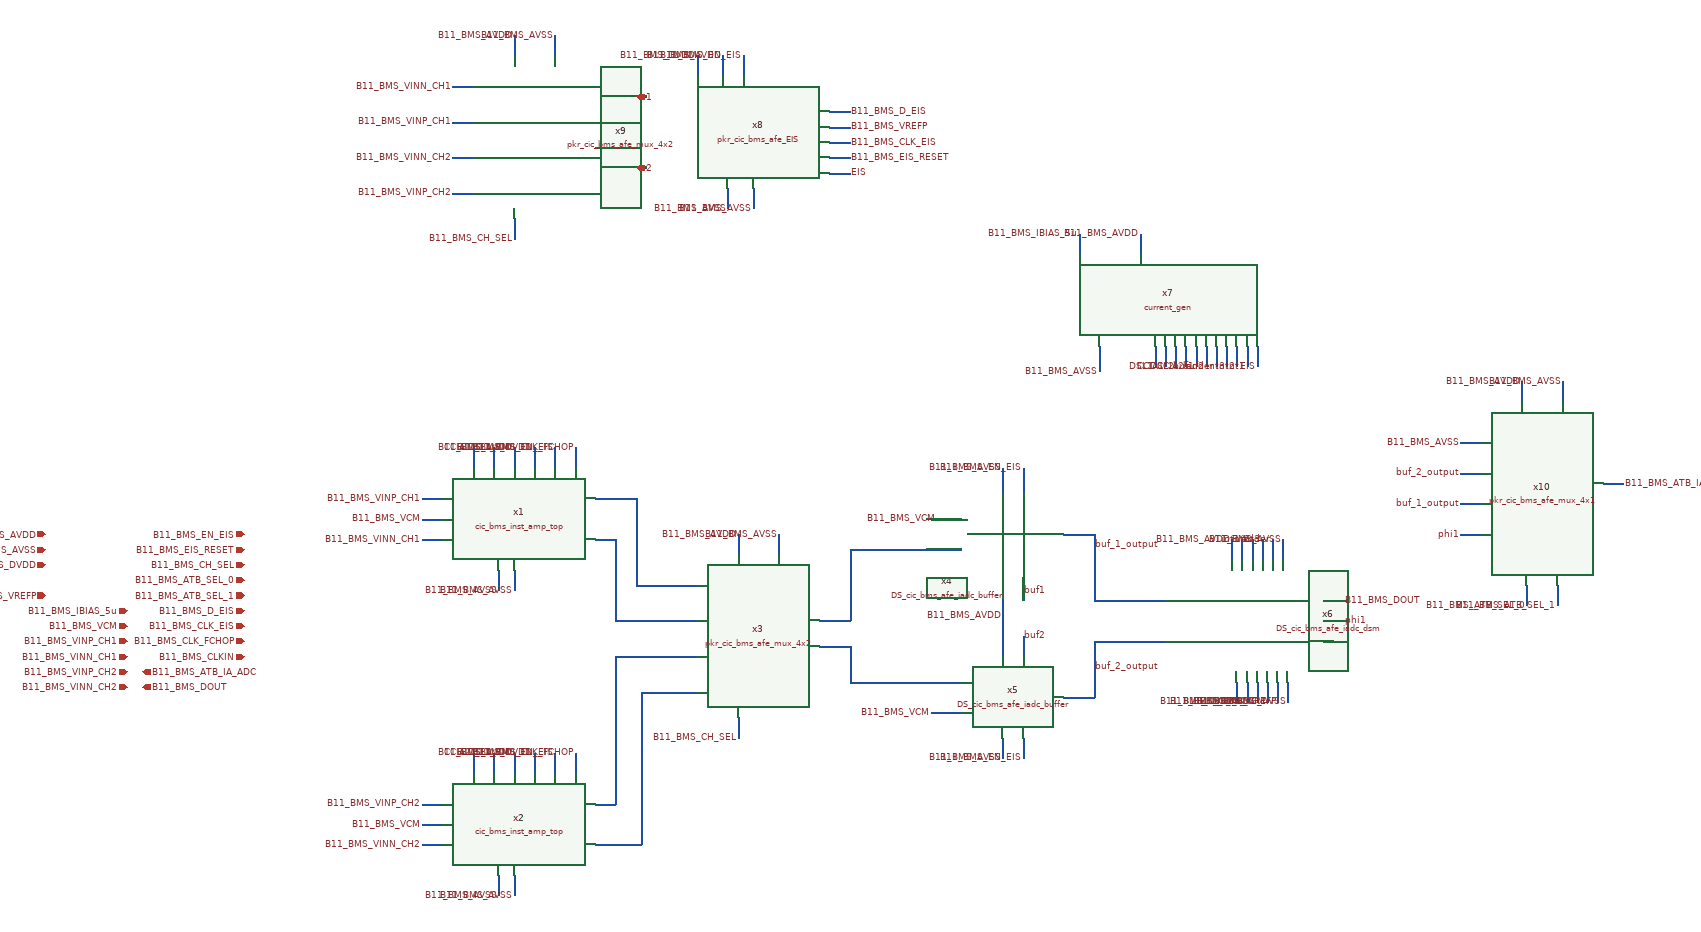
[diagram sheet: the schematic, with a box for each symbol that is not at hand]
v {xschem version=3.4.8RC file_version=1.3}
G {}
K {}
V {}
S {}
F {}
E {}
P 4 1 1090 40 {}
N 390 -460 390 -420 {
lab=B11_BMS_AVDD}
N 430 -460 430 -420 {
lab=B11_BMS_DVDD}
N 510 -460 510 -420 {
lab=B11_BMS_CLK_FCHOP}
N 550 -280 590 -280 {
lab=#net1}
N 360 -220 360 -180 {
lab=B11_BMS_AVSS}
N 550 -360 630 -360 {
lab=#net2}
N 210 -360 250 -360 {
lab=B11_BMS_VINP_CH1}
N 210 -320 250 -320 {
lab=B11_BMS_VCM}
N 210 -280 250 -280 {
lab=B11_BMS_VINN_CH1}
N 310 140 310 180 {
lab=CCIA2}
N 390 140 390 180 {
lab=B11_BMS_AVDD}
N 430 140 430 180 {
lab=B11_BMS_DVDD}
N 470 140 470 180 {
lab=B11_BMS_EN_EIS}
N 510 140 510 180 {
lab=B11_BMS_CLK_FCHOP}
N 550 320 640 320 {
lab=#net3}
N 360 380 360 420 {
lab=B11_BMS_AVSS}
N 550 240 590 240 {
lab=#net4}
N 210 240 250 240 {
lab=B11_BMS_VINP_CH2}
N 210 280 250 280 {
lab=B11_BMS_VCM}
N 210 320 250 320 {
lab=B11_BMS_VINN_CH2}
N 590 -280 590 -120 {
lab=#net1}
N 630 -360 630 -190 {
lab=#net2}
N 350 -460 350 -420 {
lab=DSL1}
N 640 30 640 320 {lab=#net3}
N 590 -40 590 240 {lab=#net4}
N 470 -460 470 -420 {
lab=B11_BMS_EN_EIS}
N 310 -460 310 -420 {
lab=CCIA1}
N 350 140 350 180 {
lab=DSL2}
N 630 -190 750 -190 {lab=#net2}
N 590 -120 750 -120 {lab=#net1}
N 590 -50 750 -50 {lab=#net4}
N 590 -50 590 -40 {lab=#net4}
N 640 20 640 30 {lab=#net3}
N 640 20 750 20 {lab=#net3}
N 830 -290 830 -250 {
lab=B11_BMS_AVDD}
N 830 70 830 110 {
lab=B11_BMS_CH_SEL}
N 910 -290 910 -250 {
lab=B11_BMS_AVSS}
N 990 -120 1050 -120 {lab=#net5}
N 990 -70 1050 -70 {lab=#net6}
N 1050 -260 1050 -120 {lab=#net5}
N 1050 -260 1270 -260 {lab=#net5}
N 1050 -70 1050 0 {lab=#net6}
N 1050 -0 1270 0 {lab=#net6}
N 1210 60 1270 60 {lab=B11_BMS_VCM}
N 1210 -320 1270 -320 {lab=B11_BMS_VCM}
N 1350 -210 1350 -50 {lab=B11_BMS_AVDD}
N 1390 -210 1390 -160 {lab=buf1}
N 1390 -90 1390 -50 {lab=buf2}
N 1350 110 1350 150 {lab=B11_BMS_AVSS}
N 1390 110 1390 150 {lab=B11_BMS_EN_EIS}
N 1470 30 1530 30 {lab=buf_2_output}
N 1470 -290 1530 -290 {lab=buf_1_output}
N 1350 -420 1350 -370 {lab=B11_BMS_AVSS}
N 1390 -420 1390 -370 {lab=B11_BMS_EN_EIS}
N 1530 -290 1530 -160 {lab=buf_1_output}
N 1530 -160 1670 -160 {lab=buf_1_output}
N 1530 -80 1530 30 {lab=buf_2_output}
N 1530 -80 1670 -80 {lab=buf_2_output}
N 1900 -280 1900 -240 {
lab=B11_BMS_AVSS}
N 1800 -280 1800 -240 {
lab=B11_BMS_AVDD}
N 1810 0 1810 40 {
lab=B11_BMS_DVDD}
N 1830 0 1830 40 {
lab=B11_BMS_CLKIN}
N 1880 -280 1880 -240 {
lab=adder}
N 1860 -280 1860 -240 {
lab=int3}
N 1840 -280 1840 -240 {
lab=int2}
N 1820 -280 1820 -240 {
lab=int1}
N 1890 0 1890 40 {
lab=B11_BMS_VREFP}
N 1870 0 1870 40 {
lab=B11_BMS_VCM}
N 1980 -160 2020 -160 {
lab=B11_BMS_DOUT}
N 1980 -120 2020 -120 {
lab=phi1}
N 1980 -80 2000 -80 {lab=#net7}
N 1910 0 1910 40 {lab=B11_BMS_AVSS}
N 1650 -660 1650 -620 {
lab=DSL1}
N 1670 -660 1670 -620 {
lab=CCIA1}
N 1690 -660 1690 -620 {
lab=DSL2}
N 1710 -660 1710 -620 {
lab=CCIA2}
N 1730 -660 1730 -620 {
lab=buf1}
N 1750 -660 1750 -620 {
lab=buf2}
N 1770 -660 1770 -620 {
lab=adder}
N 1790 -660 1790 -620 {
lab=int3}
N 1810 -660 1810 -620 {
lab=int2}
N 1830 -660 1830 -620 {
lab=int1}
N 1620 -880 1620 -840 {lab=B11_BMS_AVDD}
N 1540 -660 1540 -610 {lab=B11_BMS_AVSS}
N 1500 -880 1500 -840 {lab=B11_BMS_IBIAS_5u}
N 270 -1100 310 -1100 {
lab=B11_BMS_VINP_CH1}
N 270 -1170 310 -1170 {
lab=B11_BMS_VINN_CH1}
N 270 -960 310 -960 {
lab=B11_BMS_VINP_CH2}
N 270 -1030 310 -1030 {
lab=B11_BMS_VINN_CH2}
N 390 -910 390 -870 {
lab=B11_BMS_CH_SEL}
N 1850 -660 1850 -620 {
lab=EIS}
N 390 -1270 390 -1230 {
lab=B11_BMS_AVDD}
N 470 -1270 470 -1230 {
lab=B11_BMS_AVSS}
N 550 -1100 590 -1100 {lab=1}
N 550 -1050 620 -1050 {lab=2}
N 620 -1150 650 -1150 {lab=1}
N 590 -1100 620 -1100 {lab=1}
N 620 -1150 620 -1100 {lab=1}
N 620 -1050 620 -1010 {lab=2}
N 620 -1010 650 -1010 {lab=2}
N 840 -1230 840 -1190 {
lab=B11_BMS_EN_EIS}
N 800 -1230 800 -1190 {
lab=B11_BMS_AVDD}
N 750 -1230 750 -1190 {
lab=B11_BMS_DVDD}
N 1010 -1000 1050 -1000 {
lab=EIS}
N 1010 -1030 1050 -1030 {
lab=B11_BMS_EIS_RESET}
N 1010 -1060 1050 -1060 {
lab=B11_BMS_CLK_EIS}
N 1010 -1120 1050 -1120 {
lab=B11_BMS_D_EIS}
N 1010 -1090 1050 -1090 {
lab=B11_BMS_VREFP}
N 860 -970 860 -930 {
lab=B11_BMS_AVSS}
N 2370 -590 2370 -550 {
lab=B11_BMS_AVDD}
N 2450 -590 2450 -550 {lab=B11_BMS_AVSS}
N 2380 -190 2380 -150 {
lab=B11_BMS_ATB_SEL_0}
N 2440 -190 2440 -150 {
lab=B11_BMS_ATB_SEL_1}
N 2530 -390 2570 -390 {
lab=B11_BMS_ATB_IA_ADC}
N 2250 -410 2290 -410 {
lab=buf_2_output}
N 2250 -350 2290 -350 {
lab=buf_1_output}
N 2250 -290 2290 -290 {
lab=phi1}
N 2250 -470 2290 -470 {
lab=B11_BMS_AVSS}
N 390 380 390 420 {
lab=B11_BMS_AVSS}
N 390 -220 390 -180 {
lab=B11_BMS_AVSS}
N 810 -970 810 -930 {
lab=B11_BMS_AVSS}
N 1850 0 1850 40 {
lab=B11_BMS_AVSS}
C {TOP_LEVEL/CCIA/cic_bms_inst_amp_top.sym} 400 -320 0 0 {name=x1}
C {lab_pin.sym} 360 -180 3 0 {name=p23 sig_type=std_logic lab=B11_BMS_AVSS}
C {lab_pin.sym} 390 -460 1 0 {name=p27 sig_type=std_logic lab=B11_BMS_AVDD}
C {lab_pin.sym} 430 -460 1 0 {name=p29 sig_type=std_logic lab=B11_BMS_DVDD}
C {lab_pin.sym} 510 -460 1 0 {name=p34 sig_type=std_logic lab=B11_BMS_CLK_FCHOP}
C {lab_pin.sym} 210 -320 0 0 {name=p36 sig_type=std_logic lab=B11_BMS_VCM}
C {lab_pin.sym} 360 420 3 0 {name=p24 sig_type=std_logic lab=B11_BMS_AVSS}
C {lab_pin.sym} 390 140 1 0 {name=p25 sig_type=std_logic lab=B11_BMS_AVDD}
C {lab_pin.sym} 430 140 1 0 {name=p26 sig_type=std_logic lab=B11_BMS_DVDD}
C {lab_pin.sym} 510 140 1 0 {name=p33 sig_type=std_logic lab=B11_BMS_CLK_FCHOP}
C {lab_pin.sym} 210 280 0 0 {name=p35 sig_type=std_logic lab=B11_BMS_VCM}
C {lab_pin.sym} 470 140 1 0 {name=p44 sig_type=std_logic lab=B11_BMS_EN_EIS}
C {lab_pin.sym} 210 240 0 0 {name=p46 sig_type=std_logic lab=B11_BMS_VINP_CH2}
C {lab_pin.sym} 210 320 0 0 {name=p47 sig_type=std_logic lab=B11_BMS_VINN_CH2}
C {lab_pin.sym} 210 -360 0 0 {name=p48 sig_type=std_logic lab=B11_BMS_VINP_CH1}
C {lab_pin.sym} 210 -280 0 0 {name=p49 sig_type=std_logic lab=B11_BMS_VINN_CH1}
C {lab_pin.sym} 310 140 1 0 {name=p70 sig_type=std_logic lab=CCIA2}
C {lab_pin.sym} 350 -460 1 0 {name=p71 sig_type=std_logic lab=DSL1}
C {lab_pin.sym} 470 -460 1 0 {name=p88 sig_type=std_logic lab=B11_BMS_EN_EIS}
C {lab_pin.sym} 310 -460 1 0 {name=p1 sig_type=std_logic lab=CCIA1}
C {lab_pin.sym} 350 140 1 0 {name=p2 sig_type=std_logic lab=DSL2}
C {TOP_LEVEL/CCIA/cic_bms_inst_amp_top.sym} 400 280 0 0 {name=x2}
C {TOP_LEVEL/MUX/mux_diffrential/pkr_cic_bms_afe_mux_4x2.sym} 710 -90 0 0 {name=x3}
C {lab_pin.sym} 830 -290 1 0 {name=p11 sig_type=std_logic lab=B11_BMS_AVDD}
C {lab_pin.sym} 830 110 3 0 {name=p87 sig_type=std_logic lab=B11_BMS_CH_SEL}
C {lab_pin.sym} 910 -290 1 0 {name=p13 sig_type=std_logic lab=B11_BMS_AVSS}
C {TOP_LEVEL/Buffer/DS_cic_bms_afe_iadc_buffer.sym} 1370 -290 2 1 {name=x4}
C {TOP_LEVEL/Buffer/DS_cic_bms_afe_iadc_buffer.sym} 1370 30 0 0 {name=x5}
C {lab_pin.sym} 1350 -420 1 0 {name=p14 sig_type=std_logic lab=B11_BMS_AVSS}
C {lab_pin.sym} 1350 150 3 0 {name=p15 sig_type=std_logic lab=B11_BMS_AVSS}
C {lab_pin.sym} 1390 150 3 0 {name=p22 sig_type=std_logic lab=B11_BMS_EN_EIS}
C {lab_pin.sym} 1390 -420 1 0 {name=p28 sig_type=std_logic lab=B11_BMS_EN_EIS}
C {lab_pin.sym} 1220 -320 0 0 {name=p30 sig_type=std_logic lab=B11_BMS_VCM}
C {lab_pin.sym} 1210 60 0 0 {name=p31 sig_type=std_logic lab=B11_BMS_VCM}
C {lab_pin.sym} 1390 -180 2 0 {name=p32 sig_type=std_logic lab=buf1}
C {lab_pin.sym} 1390 -90 2 0 {name=p37 sig_type=std_logic lab=buf2}
C {lab_pin.sym} 1350 -130 0 0 {name=p42 sig_type=std_logic lab=B11_BMS_AVDD}
C {TOP_LEVEL/DSM/DS_cic_bms_afe_iadc_dsm.sym} 1830 -120 0 0 {name=x6}
C {lab_pin.sym} 1900 -280 1 0 {name=p53 sig_type=std_logic lab=B11_BMS_AVSS}
C {lab_pin.sym} 1800 -280 1 0 {name=p54 sig_type=std_logic lab=B11_BMS_AVDD}
C {lab_pin.sym} 1810 40 3 0 {name=p56 sig_type=std_logic lab=B11_BMS_DVDD}
C {lab_pin.sym} 1830 40 3 0 {name=p57 sig_type=std_logic lab=B11_BMS_CLKIN}
C {lab_pin.sym} 1860 -280 1 0 {name=p73 sig_type=std_logic lab=int3}
C {lab_pin.sym} 1880 -280 1 0 {name=p74 sig_type=std_logic lab=adder}
C {lab_pin.sym} 1820 -280 1 0 {name=p75 sig_type=std_logic lab=int1}
C {lab_pin.sym} 1840 -280 1 0 {name=p76 sig_type=std_logic lab=int2}
C {lab_pin.sym} 1890 40 3 0 {name=p79 sig_type=std_logic lab=B11_BMS_VREFP}
C {lab_pin.sym} 1870 40 3 0 {name=p80 sig_type=std_logic lab=B11_BMS_VCM}
C {lab_pin.sym} 2020 -160 2 0 {name=p81 sig_type=std_logic lab=B11_BMS_DOUT}
C {lab_pin.sym} 2020 -120 2 0 {name=p89 sig_type=std_logic lab=phi1}
C {lab_pin.sym} 1910 40 3 0 {name=p58 sig_type=std_logic lab=B11_BMS_AVSS}
C {TOP_LEVEL/Current_gen/current_gen.sym} 1600 -680 0 0 {name=x7}
C {lab_pin.sym} 1650 -620 3 0 {name=p59 sig_type=std_logic lab=DSL1}
C {lab_pin.sym} 1670 -620 3 0 {name=p60 sig_type=std_logic lab=CCIA1}
C {lab_pin.sym} 1690 -620 3 0 {name=p61 sig_type=std_logic lab=DSL2}
C {lab_pin.sym} 1710 -620 3 0 {name=p62 sig_type=std_logic lab=CCIA2}
C {lab_pin.sym} 1730 -620 3 0 {name=p63 sig_type=std_logic lab=buf1}
C {lab_pin.sym} 1750 -620 3 0 {name=p64 sig_type=std_logic lab=buf2}
C {lab_pin.sym} 1790 -620 3 0 {name=p65 sig_type=std_logic lab=int3}
C {lab_pin.sym} 1770 -620 3 0 {name=p66 sig_type=std_logic lab=adder}
C {lab_pin.sym} 1830 -620 3 0 {name=p67 sig_type=std_logic lab=int1}
C {lab_pin.sym} 1810 -620 3 0 {name=p68 sig_type=std_logic lab=int2}
C {lab_pin.sym} 1540 -610 3 0 {name=p69 sig_type=std_logic lab=B11_BMS_AVSS}
C {lab_pin.sym} 1620 -880 1 0 {name=p72 sig_type=std_logic lab=B11_BMS_AVDD}
C {lab_pin.sym} 1500 -880 1 0 {name=p77 sig_type=std_logic lab=B11_BMS_IBIAS_5u}
C {TOP_LEVEL/MUX/mux_diffrential/pkr_cic_bms_afe_mux_4x2.sym} 270 -1070 0 0 {name=x9}
C {lab_pin.sym} 270 -1100 0 0 {name=p6 sig_type=std_logic lab=B11_BMS_VINP_CH1}
C {lab_pin.sym} 270 -1170 0 0 {name=p7 sig_type=std_logic lab=B11_BMS_VINN_CH1}
C {lab_pin.sym} 270 -960 0 0 {name=p16 sig_type=std_logic lab=B11_BMS_VINP_CH2}
C {lab_pin.sym} 270 -1030 0 0 {name=p17 sig_type=std_logic lab=B11_BMS_VINN_CH2}
C {iopin.sym} -530 -290 0 0 {name=p3 lab=B11_BMS_AVDD}
C {iopin.sym} -530 -260 0 0 {name=p4 lab=B11_BMS_AVSS}
C {iopin.sym} -530 -230 0 0 {name=p5 lab=B11_BMS_DVDD
}
C {ipin.sym} -140 -230 0 0 {name=p8 lab=B11_BMS_CH_SEL

}
C {iopin.sym} -530 -170 0 0 {name=p9 lab=B11_BMS_VREFP


}
C {ipin.sym} -370 -20 0 0 {name=p10 lab=B11_BMS_VINP_CH2



}
C {ipin.sym} -370 10 0 0 {name=p12 lab=B11_BMS_VINN_CH2



}
C {ipin.sym} -370 -110 0 0 {name=p18 lab=B11_BMS_VCM}
C {ipin.sym} -140 -50 0 0 {name=p19 lab=B11_BMS_CLKIN
}
C {ipin.sym} -140 -80 0 0 {name=p20 lab=B11_BMS_CLK_FCHOP

}
C {ipin.sym} -370 -140 0 0 {name=p21 lab=B11_BMS_IBIAS_5u


}
C {opin.sym} -340 10 0 0 {name=p43 lab=B11_BMS_DOUT



}
C {ipin.sym} -140 -140 0 0 {name=p50 lab=B11_BMS_D_EIS




}
C {ipin.sym} -140 -290 0 0 {name=p52 lab=B11_BMS_EN_EIS





}
C {ipin.sym} -140 -110 0 0 {name=p84 lab=B11_BMS_CLK_EIS








}
C {ipin.sym} -140 -260 0 0 {name=p90 lab=B11_BMS_EIS_RESET








}
C {ipin.sym} -370 -80 0 0 {name=p91 lab=B11_BMS_VINP_CH1



}
C {ipin.sym} -370 -50 0 0 {name=p92 lab=B11_BMS_VINN_CH1



}
C {lab_pin.sym} 390 -870 3 0 {name=p45 sig_type=std_logic lab=B11_BMS_CH_SEL}
C {lab_pin.sym} 1850 -620 1 1 {name=p85 sig_type=std_logic lab=EIS}
C {lab_pin.sym} 390 -1270 1 0 {name=p86 sig_type=std_logic lab=B11_BMS_AVDD}
C {lab_pin.sym} 470 -1270 1 0 {name=p93 sig_type=std_logic lab=B11_BMS_AVSS}
C {opin.sym} 630 -1150 3 0 {name=p40 lab=1



}
C {opin.sym} 630 -1010 1 0 {name=p38 lab=2



}
C {TOP_LEVEL/EIS/pkr_cic_bms_afe_EIS.sym} 1090 -930 0 1 {name=x8}
C {lab_pin.sym} 840 -1230 1 0 {name=p39 sig_type=std_logic lab=B11_BMS_EN_EIS}
C {lab_pin.sym} 800 -1230 1 0 {name=p41 sig_type=std_logic lab=B11_BMS_AVDD}
C {lab_pin.sym} 750 -1230 1 0 {name=p51 sig_type=std_logic lab=B11_BMS_DVDD}
C {lab_pin.sym} 1050 -1030 0 1 {name=p78 sig_type=std_logic lab=B11_BMS_EIS_RESET}
C {lab_pin.sym} 1050 -1060 0 1 {name=p82 sig_type=std_logic lab=B11_BMS_CLK_EIS}
C {lab_pin.sym} 1050 -1120 0 1 {name=p83 sig_type=std_logic lab=B11_BMS_D_EIS}
C {lab_pin.sym} 1050 -1090 0 1 {name=p94 sig_type=std_logic lab=B11_BMS_VREFP}
C {lab_pin.sym} 1050 -1000 0 1 {name=p96 sig_type=std_logic lab=EIS}
C {lab_pin.sym} 860 -930 3 0 {name=p97 sig_type=std_logic lab=B11_BMS_AVSS}
C {TOP_LEVEL/MUX/mux4_1/pkr_cic_bms_afe_mux_4x1.sym} 2470 -390 0 0 {name=x10}
C {lab_pin.sym} 1530 -270 2 0 {name=p55 sig_type=std_logic lab=buf_1_output}
C {lab_pin.sym} 1530 -30 2 0 {name=p95 sig_type=std_logic lab=buf_2_output}
C {lab_pin.sym} 2370 -590 1 0 {name=p98 sig_type=std_logic lab=B11_BMS_AVDD}
C {lab_pin.sym} 2450 -590 1 0 {name=p99 sig_type=std_logic lab=B11_BMS_AVSS}
C {ipin.sym} -140 -170 0 0 {name=p100 lab=B11_BMS_ATB_SEL_1







}
C {ipin.sym} -140 -200 0 0 {name=p101 lab=B11_BMS_ATB_SEL_0
}
C {lab_pin.sym} 2380 -150 3 0 {name=p102 sig_type=std_logic lab=B11_BMS_ATB_SEL_0}
C {lab_pin.sym} 2440 -150 3 0 {name=p103 sig_type=std_logic lab=B11_BMS_ATB_SEL_1}
C {opin.sym} -340 -20 0 0 {name=p104 lab=B11_BMS_ATB_IA_ADC




}
C {lab_pin.sym} 2570 -390 2 0 {name=p105 sig_type=std_logic lab=B11_BMS_ATB_IA_ADC}
C {lab_pin.sym} 2250 -350 2 1 {name=p106 sig_type=std_logic lab=buf_1_output}
C {lab_pin.sym} 2250 -410 2 1 {name=p107 sig_type=std_logic lab=buf_2_output}
C {lab_pin.sym} 2250 -290 0 0 {name=p108 sig_type=std_logic lab=phi1}
C {lab_pin.sym} 2250 -470 0 0 {name=p109 sig_type=std_logic lab=B11_BMS_AVSS}
C {lab_pin.sym} 810 -930 3 0 {name=p112 sig_type=std_logic lab=B11_BMS_AVSS}
C {lab_pin.sym} 1850 40 3 0 {name=p113 sig_type=std_logic lab=B11_BMS_AVSS}
C {lab_pin.sym} 390 420 3 0 {name=p110 sig_type=std_logic lab=B11_BMS_AVSS}
C {lab_pin.sym} 390 -180 3 0 {name=p111 sig_type=std_logic lab=B11_BMS_AVSS}
